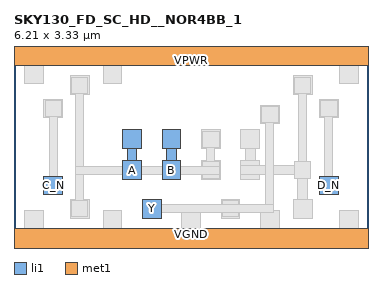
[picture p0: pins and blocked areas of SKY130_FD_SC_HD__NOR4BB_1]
MACRO SKY130_FD_SC_HD__NOR4BB_1
 CLASS CORE ;
 FOREIGN SKY130_FD_SC_HD__NOR4BB_1 0 0 ;
 SIZE 6.21 BY 3.33 ;
 ORIGIN 0 0 ;
 SYMMETRY X Y R90 ;
 SITE unit ;
  PIN VPWR
   DIRECTION INOUT ;
   USE POWER ;
   SHAPE ABUTMENT ;
    PORT
     CLASS CORE ;
       LAYER li1 ;
        RECT 0.00000000 3.09000000 6.21000000 3.57000000 ;
       LAYER met1 ;
        RECT 0.00000000 3.09000000 6.21000000 3.57000000 ;
    END
  END VPWR

  PIN VGND
   DIRECTION INOUT ;
   USE POWER ;
   SHAPE ABUTMENT ;
    PORT
     CLASS CORE ;
       LAYER li1 ;
        RECT 0.00000000 -0.24000000 6.21000000 0.24000000 ;
       LAYER met1 ;
        RECT 0.00000000 -0.24000000 6.21000000 0.24000000 ;
    END
  END VGND

  PIN Y
   DIRECTION INOUT ;
   USE SIGNAL ;
   SHAPE ABUTMENT ;
    PORT
     CLASS CORE ;
       LAYER li1 ;
        RECT 2.25000000 0.42000000 2.58000000 0.75000000 ;
    END
  END Y

  PIN B
   DIRECTION INOUT ;
   USE SIGNAL ;
   SHAPE ABUTMENT ;
    PORT
     CLASS CORE ;
       LAYER li1 ;
        RECT 2.59500000 1.09500000 2.92500000 1.42500000 ;
        RECT 2.67500000 1.42500000 2.84500000 1.63500000 ;
        RECT 2.59500000 1.63500000 2.92500000 1.96500000 ;
    END
  END B

  PIN D_N
   DIRECTION INOUT ;
   USE SIGNAL ;
   SHAPE ABUTMENT ;
    PORT
     CLASS CORE ;
       LAYER li1 ;
        RECT 5.35500000 0.82500000 5.68500000 1.15500000 ;
    END
  END D_N

  PIN A
   DIRECTION INOUT ;
   USE SIGNAL ;
   SHAPE ABUTMENT ;
    PORT
     CLASS CORE ;
       LAYER li1 ;
        RECT 1.90500000 1.09500000 2.23500000 1.42500000 ;
        RECT 1.98500000 1.42500000 2.15500000 1.63500000 ;
        RECT 1.90500000 1.63500000 2.23500000 1.96500000 ;
    END
  END A

  PIN C_N
   DIRECTION INOUT ;
   USE SIGNAL ;
   SHAPE ABUTMENT ;
    PORT
     CLASS CORE ;
       LAYER li1 ;
        RECT 0.52500000 0.82500000 0.85500000 1.15500000 ;
    END
  END C_N

 OBS
    LAYER polycont ;
     RECT 0.60500000 0.90500000 0.77500000 1.07500000 ;
     RECT 5.43500000 0.90500000 5.60500000 1.07500000 ;
     RECT 1.98500000 1.17500000 2.15500000 1.34500000 ;
     RECT 2.67500000 1.17500000 2.84500000 1.34500000 ;
     RECT 3.36500000 1.17500000 3.53500000 1.34500000 ;
     RECT 4.05500000 1.17500000 4.22500000 1.34500000 ;
     RECT 1.98500000 1.71500000 2.15500000 1.88500000 ;
     RECT 2.67500000 1.71500000 2.84500000 1.88500000 ;
     RECT 3.36500000 1.71500000 3.53500000 1.88500000 ;
     RECT 4.05500000 1.71500000 4.22500000 1.88500000 ;
     RECT 0.60500000 2.25500000 0.77500000 2.42500000 ;
     RECT 5.43500000 2.25500000 5.60500000 2.42500000 ;

    LAYER pdiffc ;
     RECT 4.40000000 2.15000000 4.57000000 2.32000000 ;
     RECT 1.06500000 2.66000000 1.23500000 2.83000000 ;
     RECT 4.97500000 2.66000000 5.14500000 2.83000000 ;
     RECT 0.26000000 2.86000000 0.43000000 3.03000000 ;
     RECT 1.64000000 2.86000000 1.81000000 3.03000000 ;
     RECT 5.78000000 2.86000000 5.95000000 3.03000000 ;

    LAYER ndiffc ;
     RECT 0.26000000 0.30000000 0.43000000 0.47000000 ;
     RECT 1.64000000 0.30000000 1.81000000 0.47000000 ;
     RECT 3.02000000 0.30000000 3.19000000 0.47000000 ;
     RECT 4.40000000 0.30000000 4.57000000 0.47000000 ;
     RECT 5.78000000 0.30000000 5.95000000 0.47000000 ;
     RECT 1.06500000 0.50000000 1.23500000 0.67000000 ;
     RECT 2.33000000 0.50000000 2.50000000 0.67000000 ;
     RECT 3.71000000 0.50000000 3.88000000 0.67000000 ;
     RECT 4.97500000 0.50000000 5.14500000 0.67000000 ;

    LAYER li1 ;
     RECT 0.00000000 -0.24000000 6.21000000 0.24000000 ;
     RECT 0.18000000 0.24000000 0.51000000 0.55000000 ;
     RECT 1.56000000 0.24000000 1.89000000 0.55000000 ;
     RECT 2.94000000 0.24000000 3.27000000 0.55000000 ;
     RECT 4.32000000 0.24000000 4.65000000 0.55000000 ;
     RECT 5.70000000 0.24000000 6.03000000 0.55000000 ;
     RECT 0.98500000 0.42000000 1.31500000 0.75000000 ;
     RECT 2.25000000 0.42000000 2.58000000 0.75000000 ;
     RECT 3.63000000 0.42000000 3.96000000 0.75000000 ;
     RECT 0.52500000 0.82500000 0.85500000 1.15500000 ;
     RECT 5.35500000 0.82500000 5.68500000 1.15500000 ;
     RECT 3.28500000 1.09500000 3.61500000 1.42500000 ;
     RECT 1.90500000 1.09500000 2.23500000 1.42500000 ;
     RECT 1.98500000 1.42500000 2.15500000 1.63500000 ;
     RECT 1.90500000 1.63500000 2.23500000 1.96500000 ;
     RECT 2.59500000 1.09500000 2.92500000 1.42500000 ;
     RECT 2.67500000 1.42500000 2.84500000 1.63500000 ;
     RECT 2.59500000 1.63500000 2.92500000 1.96500000 ;
     RECT 3.28500000 1.63500000 3.61500000 1.96500000 ;
     RECT 4.89500000 0.42000000 5.22500000 0.75000000 ;
     RECT 3.97500000 1.09500000 4.30500000 1.17500000 ;
     RECT 4.97500000 0.75000000 5.14500000 1.17500000 ;
     RECT 3.97500000 1.17500000 5.14500000 1.34500000 ;
     RECT 3.97500000 1.34500000 4.30500000 1.42500000 ;
     RECT 4.05500000 1.42500000 4.22500000 1.63500000 ;
     RECT 3.97500000 1.63500000 4.30500000 1.96500000 ;
     RECT 4.32000000 2.07000000 4.65000000 2.40000000 ;
     RECT 0.52500000 2.17500000 0.85500000 2.50500000 ;
     RECT 5.35500000 2.17500000 5.68500000 2.50500000 ;
     RECT 0.98500000 2.58000000 1.31500000 2.91000000 ;
     RECT 4.89500000 2.58000000 5.22500000 2.91000000 ;
     RECT 0.18000000 2.78000000 0.51000000 3.09000000 ;
     RECT 1.56000000 2.78000000 1.89000000 3.09000000 ;
     RECT 5.70000000 2.78000000 6.03000000 3.09000000 ;
     RECT 0.00000000 3.09000000 6.21000000 3.57000000 ;

    LAYER viali ;
     RECT 3.02000000 -0.08500000 3.19000000 0.08500000 ;
     RECT 1.06500000 0.50000000 1.23500000 0.67000000 ;
     RECT 2.33000000 0.50000000 2.50000000 0.67000000 ;
     RECT 3.71000000 0.50000000 3.88000000 0.67000000 ;
     RECT 0.60500000 0.90500000 0.77500000 1.07500000 ;
     RECT 5.43500000 0.90500000 5.60500000 1.07500000 ;
     RECT 3.36500000 1.17500000 3.53500000 1.34500000 ;
     RECT 4.97500000 1.17500000 5.14500000 1.34500000 ;
     RECT 3.36500000 1.71500000 3.53500000 1.88500000 ;
     RECT 4.40000000 2.15000000 4.57000000 2.32000000 ;
     RECT 0.60500000 2.25500000 0.77500000 2.42500000 ;
     RECT 5.43500000 2.25500000 5.60500000 2.42500000 ;
     RECT 1.06500000 2.66000000 1.23500000 2.83000000 ;
     RECT 4.97500000 2.66000000 5.14500000 2.83000000 ;
     RECT 1.64000000 3.24500000 1.81000000 3.41500000 ;

    LAYER met1 ;
     RECT 0.00000000 -0.24000000 6.21000000 0.24000000 ;
     RECT 2.27000000 0.44000000 2.56000000 0.51500000 ;
     RECT 3.65000000 0.44000000 3.94000000 0.51500000 ;
     RECT 2.27000000 0.51500000 4.55500000 0.65500000 ;
     RECT 2.27000000 0.65500000 2.56000000 0.73000000 ;
     RECT 3.65000000 0.65500000 3.94000000 0.73000000 ;
     RECT 4.41500000 0.65500000 4.55500000 2.09000000 ;
     RECT 4.34000000 2.09000000 4.63000000 2.38000000 ;
     RECT 0.54500000 0.84500000 0.83500000 1.13500000 ;
     RECT 0.62000000 1.13500000 0.76000000 2.19500000 ;
     RECT 0.54500000 2.19500000 0.83500000 2.48500000 ;
     RECT 5.37500000 0.84500000 5.66500000 1.13500000 ;
     RECT 5.45000000 1.13500000 5.59000000 2.19500000 ;
     RECT 5.37500000 2.19500000 5.66500000 2.48500000 ;
     RECT 1.00500000 0.44000000 1.29500000 0.73000000 ;
     RECT 1.08000000 0.73000000 1.22000000 1.19000000 ;
     RECT 3.30500000 1.11500000 3.59500000 1.19000000 ;
     RECT 1.08000000 1.19000000 3.59500000 1.33000000 ;
     RECT 3.30500000 1.33000000 3.59500000 1.40500000 ;
     RECT 3.38000000 1.40500000 3.52000000 1.65500000 ;
     RECT 3.30500000 1.65500000 3.59500000 1.94500000 ;
     RECT 1.08000000 1.33000000 1.22000000 2.60000000 ;
     RECT 1.00500000 2.60000000 1.29500000 2.89000000 ;
     RECT 4.91500000 1.11500000 5.20500000 1.40500000 ;
     RECT 4.99000000 1.40500000 5.13000000 2.60000000 ;
     RECT 4.91500000 2.60000000 5.20500000 2.89000000 ;
     RECT 0.00000000 3.09000000 6.21000000 3.57000000 ;

    LAYER via ;


    LAYER met2 ;


    LAYER via2 ;


    LAYER met3 ;


 END
END SKY130_FD_SC_HD__NOR4BB_1
